VERSION 5.7 ;
  NOWIREEXTENSIONATPIN ON ;
  DIVIDERCHAR "/" ;
  BUSBITCHARS "[]" ;
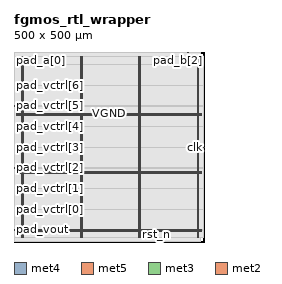
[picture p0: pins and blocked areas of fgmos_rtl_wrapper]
MACRO fgmos_rtl_wrapper
  CLASS BLOCK ;
  FOREIGN fgmos_rtl_wrapper ;
  ORIGIN 0.000 0.000 ;
  SIZE 500.000 BY 500.000 ;
  PIN VGND
    DIRECTION INOUT ;
    USE GROUND ;
    PORT
      LAYER met4 ;
        RECT 24.340 10.640 25.940 487.120 ;
    END
    PORT
      LAYER met4 ;
        RECT 177.940 10.640 179.540 487.120 ;
    END
    PORT
      LAYER met4 ;
        RECT 331.540 10.640 333.140 487.120 ;
    END
    PORT
      LAYER met4 ;
        RECT 485.140 10.640 486.740 487.120 ;
    END
    PORT
      LAYER met5 ;
        RECT 5.520 30.030 494.040 31.630 ;
    END
    PORT
      LAYER met5 ;
        RECT 5.520 183.210 494.040 184.810 ;
    END
    PORT
      LAYER met5 ;
        RECT 5.520 336.390 494.040 337.990 ;
    END
  END VGND
  PIN VPWR
    DIRECTION INOUT ;
    USE POWER ;
    PORT
      LAYER met4 ;
        RECT 21.040 10.640 22.640 487.120 ;
    END
    PORT
      LAYER met4 ;
        RECT 174.640 10.640 176.240 487.120 ;
    END
    PORT
      LAYER met4 ;
        RECT 328.240 10.640 329.840 487.120 ;
    END
    PORT
      LAYER met4 ;
        RECT 481.840 10.640 483.440 487.120 ;
    END
    PORT
      LAYER met5 ;
        RECT 5.520 26.730 494.040 28.330 ;
    END
    PORT
      LAYER met5 ;
        RECT 5.520 179.910 494.040 181.510 ;
    END
    PORT
      LAYER met5 ;
        RECT 5.520 333.090 494.040 334.690 ;
    END
  END VPWR
  PIN clk
    DIRECTION INPUT ;
    USE SIGNAL ;
    ANTENNAGATEAREA 0.852000 ;
    PORT
      LAYER met3 ;
        RECT 499.400 248.920 500.000 249.520 ;
    END
  END clk
  PIN pad_a[0]
    DIRECTION INPUT ;
    USE SIGNAL ;
    ANTENNAGATEAREA 0.213000 ;
    PORT
      LAYER met2 ;
        RECT 41.490 499.720 41.770 500.000 ;
    END
  END pad_a[0]
  PIN pad_a[1]
    DIRECTION INPUT ;
    USE SIGNAL ;
    ANTENNAGATEAREA 0.213000 ;
    PORT
      LAYER met2 ;
        RECT 124.750 499.720 125.030 500.000 ;
    END
  END pad_a[1]
  PIN pad_a[2]
    DIRECTION INPUT ;
    USE SIGNAL ;
    ANTENNAGATEAREA 0.213000 ;
    PORT
      LAYER met2 ;
        RECT 208.010 499.720 208.290 500.000 ;
    END
  END pad_a[2]
  PIN pad_b[0]
    DIRECTION INPUT ;
    USE SIGNAL ;
    ANTENNAGATEAREA 0.213000 ;
    PORT
      LAYER met2 ;
        RECT 291.270 499.720 291.550 500.000 ;
    END
  END pad_b[0]
  PIN pad_b[1]
    DIRECTION INPUT ;
    USE SIGNAL ;
    ANTENNAGATEAREA 0.213000 ;
    PORT
      LAYER met2 ;
        RECT 374.530 499.720 374.810 500.000 ;
    END
  END pad_b[1]
  PIN pad_b[2]
    DIRECTION INPUT ;
    USE SIGNAL ;
    ANTENNAGATEAREA 0.213000 ;
    PORT
      LAYER met2 ;
        RECT 457.790 499.720 458.070 500.000 ;
    END
  END pad_b[2]
  PIN pad_vctrl[0]
    DIRECTION INPUT ;
    USE SIGNAL ;
    ANTENNAGATEAREA 0.213000 ;
    PORT
      LAYER met3 ;
        RECT 0.000 85.720 0.600 86.320 ;
    END
  END pad_vctrl[0]
  PIN pad_vctrl[1]
    DIRECTION INPUT ;
    USE SIGNAL ;
    ANTENNAGATEAREA 0.213000 ;
    PORT
      LAYER met3 ;
        RECT 0.000 140.120 0.600 140.720 ;
    END
  END pad_vctrl[1]
  PIN pad_vctrl[2]
    DIRECTION INPUT ;
    USE SIGNAL ;
    ANTENNAGATEAREA 0.213000 ;
    PORT
      LAYER met3 ;
        RECT 0.000 194.520 0.600 195.120 ;
    END
  END pad_vctrl[2]
  PIN pad_vctrl[3]
    DIRECTION INPUT ;
    USE SIGNAL ;
    PORT
      LAYER met3 ;
        RECT 0.000 248.920 0.600 249.520 ;
    END
  END pad_vctrl[3]
  PIN pad_vctrl[4]
    DIRECTION INPUT ;
    USE SIGNAL ;
    PORT
      LAYER met3 ;
        RECT 0.000 303.320 0.600 303.920 ;
    END
  END pad_vctrl[4]
  PIN pad_vctrl[5]
    DIRECTION INPUT ;
    USE SIGNAL ;
    PORT
      LAYER met3 ;
        RECT 0.000 357.720 0.600 358.320 ;
    END
  END pad_vctrl[5]
  PIN pad_vctrl[6]
    DIRECTION INPUT ;
    USE SIGNAL ;
    PORT
      LAYER met3 ;
        RECT 0.000 412.120 0.600 412.720 ;
    END
  END pad_vctrl[6]
  PIN pad_vctrl[7]
    DIRECTION INPUT ;
    USE SIGNAL ;
    PORT
      LAYER met3 ;
        RECT 0.000 466.520 0.600 467.120 ;
    END
  END pad_vctrl[7]
  PIN pad_vout
    DIRECTION OUTPUT ;
    USE SIGNAL ;
    ANTENNADIFFAREA 0.702900 ;
    PORT
      LAYER met3 ;
        RECT 0.000 31.320 0.600 31.920 ;
    END
  END pad_vout
  PIN rst_n
    DIRECTION INPUT ;
    USE SIGNAL ;
    ANTENNAGATEAREA 0.213000 ;
    PORT
      LAYER met2 ;
        RECT 374.530 0.000 374.810 0.280 ;
    END
  END rst_n
  OBS
      LAYER nwell ;
        RECT 5.330 10.795 494.230 487.070 ;
      LAYER li1 ;
        RECT 5.520 10.795 494.040 486.965 ;
      LAYER met1 ;
        RECT 1.910 10.640 494.040 487.120 ;
      LAYER met2 ;
        RECT 1.930 499.440 41.210 499.720 ;
        RECT 42.050 499.440 124.470 499.720 ;
        RECT 125.310 499.440 207.730 499.720 ;
        RECT 208.570 499.440 290.990 499.720 ;
        RECT 291.830 499.440 374.250 499.720 ;
        RECT 375.090 499.440 457.510 499.720 ;
        RECT 458.350 499.440 490.730 499.720 ;
        RECT 1.930 0.560 490.730 499.440 ;
        RECT 1.930 0.280 374.250 0.560 ;
        RECT 375.090 0.280 490.730 0.560 ;
      LAYER met3 ;
        RECT 0.600 467.520 499.400 487.045 ;
        RECT 1.000 466.120 499.400 467.520 ;
        RECT 0.600 413.120 499.400 466.120 ;
        RECT 1.000 411.720 499.400 413.120 ;
        RECT 0.600 358.720 499.400 411.720 ;
        RECT 1.000 357.320 499.400 358.720 ;
        RECT 0.600 304.320 499.400 357.320 ;
        RECT 1.000 302.920 499.400 304.320 ;
        RECT 0.600 249.920 499.400 302.920 ;
        RECT 1.000 248.520 499.000 249.920 ;
        RECT 0.600 195.520 499.400 248.520 ;
        RECT 1.000 194.120 499.400 195.520 ;
        RECT 0.600 141.120 499.400 194.120 ;
        RECT 1.000 139.720 499.400 141.120 ;
        RECT 0.600 86.720 499.400 139.720 ;
        RECT 1.000 85.320 499.400 86.720 ;
        RECT 0.600 32.320 499.400 85.320 ;
        RECT 1.000 30.920 499.400 32.320 ;
        RECT 0.600 10.715 499.400 30.920 ;
  END
END fgmos_rtl_wrapper
END LIBRARY

